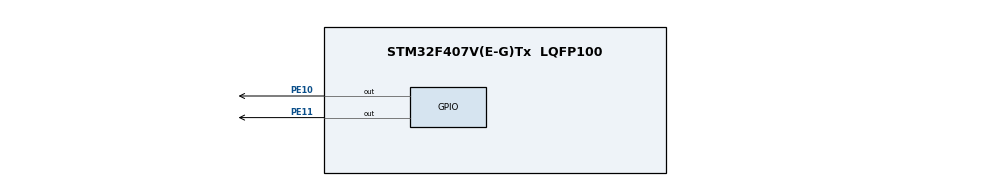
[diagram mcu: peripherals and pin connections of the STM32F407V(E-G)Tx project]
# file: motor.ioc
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Mcu.Family=STM32F4
Mcu.Name=STM32F407V(E-G)Tx
Mcu.Package=LQFP100
NVIC.PriorityGroup=NVIC_PRIORITYGROUP_0
PE10.Signal=GPIO_Output
PE11.Signal=GPIO_Output
ProjectManager.HeapSize=0x200
ProjectManager.StackSize=0x400
ProjectManager.TargetToolchain=STM32CubeIDE
RCC.48MHZClocksFreq_Value=14285714.285714285
RCC.AHBFreq_Value=25000000
RCC.APB1CLKDivider=RCC_HCLK_DIV4
RCC.APB1Freq_Value=6250000
RCC.APB1TimFreq_Value=12500000
RCC.APB2CLKDivider=RCC_HCLK_DIV2
RCC.APB2Freq_Value=12500000
RCC.APB2TimFreq_Value=25000000
RCC.CortexFreq_Value=25000000
RCC.HCLKFreq_Value=25000000
RCC.HSE_VALUE=8000000
RCC.HSI_VALUE=16000000
RCC.LSE_VALUE=32768
RCC.PLLM=8
RCC.PLLN=50
RCC.PLLP=RCC_PLLP_DIV4
RCC.PLLQ=7
RCC.SYSCLKFreq_VALUE=25000000
RCC.SYSCLKSource=RCC_SYSCLKSOURCE_PLLCLK
RCC.VCOOutputFreq_Value=100000000
board=STM32F407G-DISC1

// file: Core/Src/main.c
/* USER CODE BEGIN Header */
/**
  ******************************************************************************
  * @file           : main.c
  * @brief          : DC Motor Control using L298N (No PWM)
  ******************************************************************************
  */
/* USER CODE END Header */

#include "main.h"

/* USER CODE BEGIN Includes */
#include <stdio.h>
/* USER CODE END Includes */

/* USER CODE BEGIN PD */
#define MOTOR_IN1_PORT GPIOE
#define MOTOR_IN1_PIN  GPIO_PIN_10

#define MOTOR_IN2_PORT GPIOE
#define MOTOR_IN2_PIN  GPIO_PIN_11
/* USER CODE END PD */

/* Function prototypes */
void SystemClock_Config(void);
static void MX_GPIO_Init(void);

/* USER CODE BEGIN 0 */

void Motor_Forward(void)
{
    HAL_GPIO_WritePin(MOTOR_IN1_PORT, MOTOR_IN1_PIN, GPIO_PIN_SET);
    HAL_GPIO_WritePin(MOTOR_IN2_PORT, MOTOR_IN2_PIN, GPIO_PIN_RESET);
}

void Motor_Backward(void)
{
    HAL_GPIO_WritePin(MOTOR_IN1_PORT, MOTOR_IN1_PIN, GPIO_PIN_RESET);
    HAL_GPIO_WritePin(MOTOR_IN2_PORT, MOTOR_IN2_PIN, GPIO_PIN_SET);
}

void Motor_Stop(void)
{
    HAL_GPIO_WritePin(MOTOR_IN1_PORT, MOTOR_IN1_PIN, GPIO_PIN_RESET);
    HAL_GPIO_WritePin(MOTOR_IN2_PORT, MOTOR_IN2_PIN, GPIO_PIN_RESET);
}

/* USER CODE END 0 */

int main(void)
{
    HAL_Init();
    SystemClock_Config();
    MX_GPIO_Init();

    while (1)
    {
        Motor_Forward();      // Rotate forward
        HAL_Delay(3000);

        Motor_Stop();         // Stop
        HAL_Delay(2000);

        Motor_Backward();     // Rotate backward
        HAL_Delay(3000);

        Motor_Stop();         // Stop
        HAL_Delay(2000);
    }
}

/* ================= GPIO INIT ================= */
static void MX_GPIO_Init(void)
{
    GPIO_InitTypeDef GPIO_InitStruct = {0};

    __HAL_RCC_GPIOE_CLK_ENABLE();

    GPIO_InitStruct.Pin = MOTOR_IN1_PIN | MOTOR_IN2_PIN;
    GPIO_InitStruct.Mode = GPIO_MODE_OUTPUT_PP;
    GPIO_InitStruct.Pull = GPIO_NOPULL;
    GPIO_InitStruct.Speed = GPIO_SPEED_FREQ_LOW;
    HAL_GPIO_Init(GPIOE, &GPIO_InitStruct);
}

/* ================= SYSTEM CLOCK ================= */
void SystemClock_Config(void)
{
    RCC_OscInitTypeDef RCC_OscInitStruct = {0};
    RCC_ClkInitTypeDef RCC_ClkInitStruct = {0};

    __HAL_RCC_PWR_CLK_ENABLE();
    __HAL_PWR_VOLTAGESCALING_CONFIG(PWR_REGULATOR_VOLTAGE_SCALE1);

    RCC_OscInitStruct.OscillatorType = RCC_OSCILLATORTYPE_HSE;
    RCC_OscInitStruct.HSEState = RCC_HSE_ON;
    RCC_OscInitStruct.PLL.PLLState = RCC_PLL_ON;
    RCC_OscInitStruct.PLL.PLLSource = RCC_PLLSOURCE_HSE;
    RCC_OscInitStruct.PLL.PLLM = 4;
    RCC_OscInitStruct.PLL.PLLN = 168;
    RCC_OscInitStruct.PLL.PLLP = RCC_PLLP_DIV2;
    RCC_OscInitStruct.PLL.PLLQ = 7;
    HAL_RCC_OscConfig(&RCC_OscInitStruct);

    RCC_ClkInitStruct.ClockType = RCC_CLOCKTYPE_SYSCLK |
                                 RCC_CLOCKTYPE_HCLK |
                                 RCC_CLOCKTYPE_PCLK1 |
                                 RCC_CLOCKTYPE_PCLK2;
    RCC_ClkInitStruct.SYSCLKSource = RCC_SYSCLKSOURCE_PLLCLK;
    RCC_ClkInitStruct.AHBCLKDivider = RCC_SYSCLK_DIV1;
    RCC_ClkInitStruct.APB1CLKDivider = RCC_HCLK_DIV4;
    RCC_ClkInitStruct.APB2CLKDivider = RCC_HCLK_DIV2;
    HAL_RCC_ClockConfig(&RCC_ClkInitStruct, FLASH_LATENCY_5);
}
